VERSION 5.7 ;
  NOWIREEXTENSIONATPIN ON ;
  DIVIDERCHAR "/" ;
  BUSBITCHARS "[]" ;
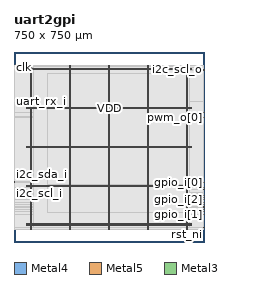
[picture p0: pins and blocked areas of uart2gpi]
MACRO uart2gpi
  CLASS BLOCK ;
  FOREIGN uart2gpi ;
  ORIGIN 0.000 0.000 ;
  SIZE 750.000 BY 750.000 ;
  PIN VDD
    DIRECTION INOUT ;
    USE POWER ;
    PORT
      LAYER Metal4 ;
        RECT 65.920 50.660 67.520 698.060 ;
    END
    PORT
      LAYER Metal4 ;
        RECT 219.520 50.660 221.120 698.060 ;
    END
    PORT
      LAYER Metal4 ;
        RECT 373.120 50.660 374.720 698.060 ;
    END
    PORT
      LAYER Metal4 ;
        RECT 526.720 50.660 528.320 698.060 ;
    END
    PORT
      LAYER Metal4 ;
        RECT 680.320 50.660 681.920 698.060 ;
    END
    PORT
      LAYER Metal5 ;
        RECT 50.400 66.810 700.000 68.410 ;
    END
    PORT
      LAYER Metal5 ;
        RECT 50.400 219.990 700.000 221.590 ;
    END
    PORT
      LAYER Metal5 ;
        RECT 50.400 373.170 700.000 374.770 ;
    END
    PORT
      LAYER Metal5 ;
        RECT 50.400 526.350 700.000 527.950 ;
    END
    PORT
      LAYER Metal5 ;
        RECT 50.400 679.530 700.000 681.130 ;
    END
  END VDD
  PIN VSS
    DIRECTION INOUT ;
    USE GROUND ;
    PORT
      LAYER Metal4 ;
        RECT 69.220 50.660 70.820 698.060 ;
    END
    PORT
      LAYER Metal4 ;
        RECT 222.820 50.660 224.420 698.060 ;
    END
    PORT
      LAYER Metal4 ;
        RECT 376.420 50.660 378.020 698.060 ;
    END
    PORT
      LAYER Metal4 ;
        RECT 530.020 50.660 531.620 698.060 ;
    END
    PORT
      LAYER Metal4 ;
        RECT 683.620 50.660 685.220 698.060 ;
    END
    PORT
      LAYER Metal5 ;
        RECT 50.400 70.110 700.000 71.710 ;
    END
    PORT
      LAYER Metal5 ;
        RECT 50.400 223.290 700.000 224.890 ;
    END
    PORT
      LAYER Metal5 ;
        RECT 50.400 376.470 700.000 378.070 ;
    END
    PORT
      LAYER Metal5 ;
        RECT 50.400 529.650 700.000 531.250 ;
    END
    PORT
      LAYER Metal5 ;
        RECT 50.400 682.830 700.000 684.430 ;
    END
  END VSS
  PIN clk
    DIRECTION INPUT ;
    USE SIGNAL ;
    ANTENNAGATEAREA 4.738000 ;
    ANTENNADIFFAREA 0.410400 ;
    PORT
      LAYER Metal3 ;
        RECT 0.000 689.920 0.560 690.480 ;
    END
  END clk
  PIN gpio_i[0]
    DIRECTION INPUT ;
    USE SIGNAL ;
    ANTENNAGATEAREA 0.606000 ;
    ANTENNADIFFAREA 0.410400 ;
    PORT
      LAYER Metal3 ;
        RECT 749.440 235.200 750.000 235.760 ;
    END
  END gpio_i[0]
  PIN gpio_i[1]
    DIRECTION INPUT ;
    USE SIGNAL ;
    ANTENNAGATEAREA 0.606000 ;
    ANTENNADIFFAREA 0.410400 ;
    PORT
      LAYER Metal3 ;
        RECT 749.440 108.640 750.000 109.200 ;
    END
  END gpio_i[1]
  PIN gpio_i[2]
    DIRECTION INPUT ;
    USE SIGNAL ;
    ANTENNAGATEAREA 0.606000 ;
    ANTENNADIFFAREA 0.410400 ;
    PORT
      LAYER Metal3 ;
        RECT 749.440 166.880 750.000 167.440 ;
    END
  END gpio_i[2]
  PIN gpio_i[3]
    DIRECTION INPUT ;
    USE SIGNAL ;
    ANTENNAGATEAREA 0.606000 ;
    ANTENNADIFFAREA 0.410400 ;
    PORT
      LAYER Metal3 ;
        RECT 749.440 120.960 750.000 121.520 ;
    END
  END gpio_i[3]
  PIN gpio_o[0]
    DIRECTION OUTPUT ;
    USE SIGNAL ;
    ANTENNADIFFAREA 0.897600 ;
    PORT
      LAYER Metal3 ;
        RECT 749.440 208.320 750.000 208.880 ;
    END
  END gpio_o[0]
  PIN gpio_o[1]
    DIRECTION OUTPUT ;
    USE SIGNAL ;
    ANTENNADIFFAREA 0.897600 ;
    PORT
      LAYER Metal3 ;
        RECT 749.440 148.960 750.000 149.520 ;
    END
  END gpio_o[1]
  PIN gpio_o[2]
    DIRECTION OUTPUT ;
    USE SIGNAL ;
    ANTENNADIFFAREA 0.897600 ;
    PORT
      LAYER Metal3 ;
        RECT 749.440 184.800 750.000 185.360 ;
    END
  END gpio_o[2]
  PIN gpio_o[3]
    DIRECTION OUTPUT ;
    USE SIGNAL ;
    ANTENNADIFFAREA 0.897600 ;
    PORT
      LAYER Metal3 ;
        RECT 749.440 128.800 750.000 129.360 ;
    END
  END gpio_o[3]
  PIN gpio_oe[0]
    DIRECTION OUTPUT ;
    USE SIGNAL ;
    ANTENNADIFFAREA 0.897600 ;
    PORT
      LAYER Metal3 ;
        RECT 749.440 213.920 750.000 214.480 ;
    END
  END gpio_oe[0]
  PIN gpio_oe[1]
    DIRECTION OUTPUT ;
    USE SIGNAL ;
    ANTENNADIFFAREA 0.897600 ;
    PORT
      LAYER Metal3 ;
        RECT 749.440 155.680 750.000 156.240 ;
    END
  END gpio_oe[1]
  PIN gpio_oe[2]
    DIRECTION OUTPUT ;
    USE SIGNAL ;
    ANTENNADIFFAREA 0.897600 ;
    PORT
      LAYER Metal3 ;
        RECT 749.440 176.960 750.000 177.520 ;
    END
  END gpio_oe[2]
  PIN gpio_oe[3]
    DIRECTION OUTPUT ;
    USE SIGNAL ;
    ANTENNADIFFAREA 0.897600 ;
    PORT
      LAYER Metal3 ;
        RECT 749.440 137.760 750.000 138.320 ;
    END
  END gpio_oe[3]
  PIN i2c_scl_i
    DIRECTION INPUT ;
    USE SIGNAL ;
    ANTENNAGATEAREA 4.853000 ;
    ANTENNADIFFAREA 2.462400 ;
    PORT
      LAYER Metal3 ;
        RECT 0.000 192.640 0.560 193.200 ;
    END
  END i2c_scl_i
  PIN i2c_scl_o
    DIRECTION OUTPUT ;
    USE SIGNAL ;
    ANTENNADIFFAREA 0.360800 ;
    PORT
      LAYER Metal3 ;
        RECT 749.440 678.720 750.000 679.280 ;
    END
  END i2c_scl_o
  PIN i2c_scl_oe
    DIRECTION OUTPUT ;
    USE SIGNAL ;
    ANTENNADIFFAREA 0.748000 ;
    PORT
      LAYER Metal3 ;
        RECT 0.000 179.200 0.560 179.760 ;
    END
  END i2c_scl_oe
  PIN i2c_sda_i
    DIRECTION INPUT ;
    USE SIGNAL ;
    ANTENNAGATEAREA 9.226000 ;
    ANTENNADIFFAREA 3.693600 ;
    PORT
      LAYER Metal3 ;
        RECT 0.000 236.320 0.560 236.880 ;
    END
  END i2c_sda_i
  PIN i2c_sda_o
    DIRECTION OUTPUT ;
    USE SIGNAL ;
    ANTENNADIFFAREA 0.360800 ;
    PORT
      LAYER Metal3 ;
        RECT 749.440 680.960 750.000 681.520 ;
    END
  END i2c_sda_o
  PIN i2c_sda_oe
    DIRECTION OUTPUT ;
    USE SIGNAL ;
    ANTENNADIFFAREA 0.748000 ;
    PORT
      LAYER Metal3 ;
        RECT 0.000 180.320 0.560 180.880 ;
    END
  END i2c_sda_oe
  PIN pwm_o[0]
    DIRECTION OUTPUT ;
    USE SIGNAL ;
    ANTENNADIFFAREA 0.897600 ;
    PORT
      LAYER Metal3 ;
        RECT 749.440 492.800 750.000 493.360 ;
    END
  END pwm_o[0]
  PIN pwm_o[1]
    DIRECTION OUTPUT ;
    USE SIGNAL ;
    ANTENNADIFFAREA 0.897600 ;
    PORT
      LAYER Metal3 ;
        RECT 749.440 511.840 750.000 512.400 ;
    END
  END pwm_o[1]
  PIN rst_ni
    DIRECTION INPUT ;
    USE SIGNAL ;
    ANTENNAGATEAREA 0.396000 ;
    ANTENNADIFFAREA 0.410400 ;
    PORT
      LAYER Metal3 ;
        RECT 749.440 57.120 750.000 57.680 ;
    END
  END rst_ni
  PIN uart_rx_i
    DIRECTION INPUT ;
    USE SIGNAL ;
    ANTENNAGATEAREA 1.570500 ;
    ANTENNADIFFAREA 0.820800 ;
    PORT
      LAYER Metal3 ;
        RECT 0.000 554.400 0.560 554.960 ;
    END
  END uart_rx_i
  PIN uart_tx_o
    DIRECTION OUTPUT ;
    USE SIGNAL ;
    ANTENNADIFFAREA 1.121800 ;
    PORT
      LAYER Metal3 ;
        RECT 0.000 555.520 0.560 556.080 ;
    END
  END uart_tx_o
  OBS
      LAYER Nwell ;
        RECT 49.970 50.530 700.430 698.190 ;
      LAYER Metal1 ;
        RECT 50.400 50.660 700.000 698.060 ;
      LAYER Metal2 ;
        RECT 0.140 50.770 749.700 697.950 ;
      LAYER Metal3 ;
        RECT 0.090 690.780 749.750 697.900 ;
        RECT 0.860 689.620 749.750 690.780 ;
        RECT 0.090 681.820 749.750 689.620 ;
        RECT 0.090 680.660 749.140 681.820 ;
        RECT 0.090 679.580 749.750 680.660 ;
        RECT 0.090 678.420 749.140 679.580 ;
        RECT 0.090 556.380 749.750 678.420 ;
        RECT 0.860 554.100 749.750 556.380 ;
        RECT 0.090 512.700 749.750 554.100 ;
        RECT 0.090 511.540 749.140 512.700 ;
        RECT 0.090 493.660 749.750 511.540 ;
        RECT 0.090 492.500 749.140 493.660 ;
        RECT 0.090 237.180 749.750 492.500 ;
        RECT 0.860 236.060 749.750 237.180 ;
        RECT 0.860 236.020 749.140 236.060 ;
        RECT 0.090 234.900 749.140 236.020 ;
        RECT 0.090 214.780 749.750 234.900 ;
        RECT 0.090 213.620 749.140 214.780 ;
        RECT 0.090 209.180 749.750 213.620 ;
        RECT 0.090 208.020 749.140 209.180 ;
        RECT 0.090 193.500 749.750 208.020 ;
        RECT 0.860 192.340 749.750 193.500 ;
        RECT 0.090 185.660 749.750 192.340 ;
        RECT 0.090 184.500 749.140 185.660 ;
        RECT 0.090 181.180 749.750 184.500 ;
        RECT 0.860 178.900 749.750 181.180 ;
        RECT 0.090 177.820 749.750 178.900 ;
        RECT 0.090 176.660 749.140 177.820 ;
        RECT 0.090 167.740 749.750 176.660 ;
        RECT 0.090 166.580 749.140 167.740 ;
        RECT 0.090 156.540 749.750 166.580 ;
        RECT 0.090 155.380 749.140 156.540 ;
        RECT 0.090 149.820 749.750 155.380 ;
        RECT 0.090 148.660 749.140 149.820 ;
        RECT 0.090 138.620 749.750 148.660 ;
        RECT 0.090 137.460 749.140 138.620 ;
        RECT 0.090 129.660 749.750 137.460 ;
        RECT 0.090 128.500 749.140 129.660 ;
        RECT 0.090 121.820 749.750 128.500 ;
        RECT 0.090 120.660 749.140 121.820 ;
        RECT 0.090 109.500 749.750 120.660 ;
        RECT 0.090 108.340 749.140 109.500 ;
        RECT 0.090 57.980 749.750 108.340 ;
        RECT 0.090 56.820 749.140 57.980 ;
        RECT 0.090 50.820 749.750 56.820 ;
      LAYER Metal4 ;
        RECT 75.740 58.890 219.220 691.510 ;
        RECT 221.420 58.890 222.520 691.510 ;
        RECT 224.720 58.890 372.820 691.510 ;
        RECT 375.020 58.890 376.120 691.510 ;
        RECT 378.320 58.890 526.420 691.510 ;
        RECT 528.620 58.890 529.720 691.510 ;
        RECT 531.920 58.890 680.020 691.510 ;
        RECT 682.220 58.890 683.320 691.510 ;
        RECT 685.520 58.890 694.260 691.510 ;
      LAYER Metal5 ;
        RECT 131.100 531.850 683.140 663.970 ;
        RECT 131.100 528.550 683.140 529.050 ;
        RECT 131.100 378.670 683.140 525.750 ;
        RECT 131.100 375.370 683.140 375.870 ;
        RECT 131.100 225.490 683.140 372.570 ;
        RECT 131.100 222.190 683.140 222.690 ;
        RECT 131.100 117.230 683.140 219.390 ;
  END
END uart2gpi
END LIBRARY

